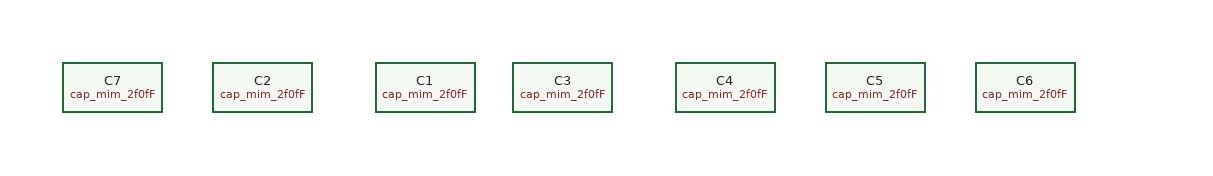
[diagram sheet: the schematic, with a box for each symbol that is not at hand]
v {xschem version=3.4.8RC file_version=1.3}
G {}
K {}
V {}
S {}
F {}
E {}
C {symbols/cap_mim_2f0fF.sym} -110 -20 0 0 {name=C1
W=1e-6
L=1e-6
model=cap_mim_2f0fF
spiceprefix=X
m=1}
C {symbols/cap_mim_2f0fF.sym} -240 -20 0 0 {name=C2
W=1e-6
L=1e-6
model=cap_mim_2f0fF
spiceprefix=X
m=1}
C {symbols/cap_mim_2f0fF.sym} 0 -20 0 0 {name=C3
W=1e-6
L=1e-6
model=cap_mim_2f0fF
spiceprefix=X
m=1}
C {symbols/cap_mim_2f0fF.sym} 130 -20 0 0 {name=C4
W=1e-6
L=1e-6
model=cap_mim_2f0fF
spiceprefix=X
m=1}
C {symbols/cap_mim_2f0fF.sym} 250 -20 0 0 {name=C5
W=1e-6
L=1e-6
model=cap_mim_2f0fF
spiceprefix=X
m=1}
C {symbols/cap_mim_2f0fF.sym} 370 -20 0 0 {name=C6
W=1e-6
L=1e-6
model=cap_mim_2f0fF
spiceprefix=X
m=1}
C {symbols/cap_mim_2f0fF.sym} -360 -20 0 0 {name=C7
W=1e-6
L=1e-6
model=cap_mim_2f0fF
spiceprefix=X
m=1}
